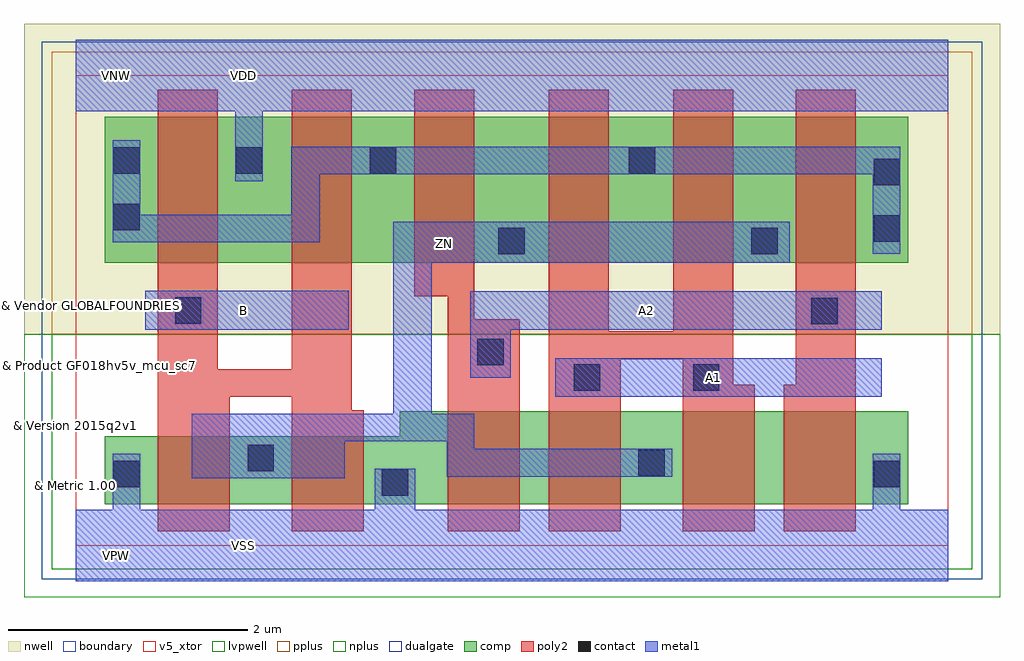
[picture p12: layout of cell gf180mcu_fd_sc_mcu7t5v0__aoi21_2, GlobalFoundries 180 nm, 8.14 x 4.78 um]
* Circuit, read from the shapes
.subckt gf180mcu_fd_sc_mcu7t5v0__aoi21_2 A1 A2 B VDD VNW VSS ZN
XM1 ZN B VSS VSUBS nfet_05v0 w=0.565u l=0.6u m=2
XM2 n1 A2 VSS VSUBS nfet_05v0 w=0.775u l=0.6u
XM3 ZN A1 n1 VSUBS nfet_05v0 w=0.775u l=0.6u
XM4 n2 A1 ZN VSUBS nfet_05v0 w=0.775u l=0.6u
XM5 VSS A2 n2 VSUBS nfet_05v0 w=0.775u l=0.6u
XM6 VDD B n3 VNW pfet_05v0 w=1.215u l=0.5u m=2
XM7 ZN A2 n3 VNW pfet_05v0 w=1.215u l=0.5u m=2
XM8 n3 A1 ZN VNW pfet_05v0 w=1.215u l=0.5u m=2
.ends

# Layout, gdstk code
import gdstk
lib = gdstk.Library(unit=1e-6, precision=1e-09)
def R(c, l, rs):  # rectangles x0, y0, x1, y1
    for r in rs: c.add(gdstk.rectangle(r[:2], r[2:], *l))
def P(c, l, *ps):  # polygons
    for p in ps: c.add(gdstk.Polygon(p, *l))
boundary = (0, 0)
nwell = (21, 0)
comp = (22, 0)
poly2 = (30, 0)
pplus = (31, 0)
nplus = (32, 0)
contact = (33, 0)
metal1 = (34, 0)
dualgate = (55, 0)
v5_xtor = (112, 1)
lvpwell = (204, 0)

gf180mcu_fd_sc_mcu7t5v0_ = lib.new_cell('gf180mcu_fd_sc_mcu7t5v0__aoi21_2')
R(gf180mcu_fd_sc_mcu7t5v0_, boundary, [(0,0,7.28,3.92)])
R(gf180mcu_fd_sc_mcu7t5v0_, nwell, [(-0.43,1.76,7.71,4.35)])
R(gf180mcu_fd_sc_mcu7t5v0_, comp, [(0.245,2.36,6.945,3.575)])
P(gf180mcu_fd_sc_mcu7t5v0_, comp, [(0.245,0.345),(0.245,0.91),(2.705,0.91),(2.705,1.12),(6.945,1.12),(6.945,0.345)])
P(gf180mcu_fd_sc_mcu7t5v0_, poly2, [(0.685,0.12),(0.685,3.8),(1.185,3.8),(1.185,1.47),(1.805,1.47),(1.805,3.8),(2.305,3.8),(2.305,1.13),(2.405,1.13),(2.405,0.12),(1.805,0.12),(1.805,1.24),(1.285,1.24),(1.285,0.12)],
  [(3.105,0.12),(3.105,2.08),(2.825,2.08),(2.825,3.8),(3.325,3.8),(3.325,1.885),(3.705,1.885),(3.705,0.12)],
  [(3.945,0.12),(3.945,3.8),(4.445,3.8),(4.445,1.785),(4.985,1.785),(4.985,3.8),(5.485,3.8),(5.485,1.34),(5.665,1.34),(5.665,0.12),(5.065,0.12),(5.065,1.555),(4.545,1.555),(4.545,0.12)],
  [(5.905,0.12),(5.905,1.34),(6.005,1.34),(6.005,3.8),(6.505,3.8),(6.505,0.12)])
R(gf180mcu_fd_sc_mcu7t5v0_, pplus, [(-0.2,1.76,7.48,4.12)])
R(gf180mcu_fd_sc_mcu7t5v0_, nplus, [(-0.2,-0.2,7.48,1.76)])
R(gf180mcu_fd_sc_mcu7t5v0_, contact, [(2.555,0.415,2.775,0.635), (0.315,0.485,0.535,0.705), (6.655,0.485,6.875,0.705), (4.695,0.58,4.915,0.8), (1.435,0.62,1.655,0.84), (4.155,1.29,4.375,1.51), (5.15,1.29,5.37,1.51), (3.35,1.505,3.57,1.725), (6.135,1.845,6.355,2.065), (0.83,1.85,1.05,2.07), (3.525,2.43,3.745,2.65), (5.635,2.43,5.855,2.65), (6.655,2.535,6.875,2.755), (0.315,2.63,0.535,2.85), (6.655,3.005,6.875,3.225), (0.315,3.1,0.535,3.32), (1.335,3.1,1.555,3.32), (2.455,3.1,2.675,3.32), (4.615,3.1,4.835,3.32)])
R(gf180mcu_fd_sc_mcu7t5v0_, metal1, [(4,1.24,6.725,1.56), (0.58,1.8,2.28,2.125)])
P(gf180mcu_fd_sc_mcu7t5v0_, metal1, [(0.97,0.56),(0.97,1.1),(2.65,1.1),(2.65,2.7),(5.955,2.7),(5.955,2.36),(2.97,2.36),(2.97,1.1),(3.325,1.1),(3.325,0.805),(4.975,0.805),(4.975,0.575),(3.095,0.575),(3.095,0.87),(2.245,0.87),(2.245,0.56)],
  [(3.29,1.4),(3.29,2.12),(6.725,2.12),(6.725,1.8),(3.63,1.8),(3.63,1.4)],
  [(6.65,2.435),(6.65,3.095),(2.035,3.095),(2.035,2.53),(0.31,2.53),(0.31,3.38),(0.54,3.38),(0.54,2.76),(1.8,2.76),(1.8,3.325),(6.88,3.325),(6.88,2.435)],
  [(0,-0.3),(0,0.3),(0.31,0.3),(0.31,0.765),(0.54,0.765),(0.54,0.3),(2.495,0.3),(2.495,0.64),(2.835,0.64),(2.835,0.3),(6.65,0.3),(6.65,0.765),(6.88,0.765),(6.88,0.3),(7.28,0.3),(7.28,-0.3)],
  [(1.33,3.04),(1.33,3.62),(0,3.62),(0,4.22),(7.28,4.22),(7.28,3.62),(1.56,3.62),(1.56,3.04)])
R(gf180mcu_fd_sc_mcu7t5v0_, dualgate, [(-0.28,-0.28,7.56,4.2)])
R(gf180mcu_fd_sc_mcu7t5v0_, v5_xtor, [(0,0,7.28,3.92)])
R(gf180mcu_fd_sc_mcu7t5v0_, lvpwell, [(-0.43,-0.43,7.71,1.76)])
gf180mcu_fd_sc_mcu7t5v0_.add(gdstk.Label('B', (1.4,1.96), layer=34, texttype=10))
gf180mcu_fd_sc_mcu7t5v0_.add(gdstk.Label('VDD', (1.4,3.92), layer=34, texttype=10))
gf180mcu_fd_sc_mcu7t5v0_.add(gdstk.Label('VSS', (1.4,0), layer=34, texttype=10))
gf180mcu_fd_sc_mcu7t5v0_.add(gdstk.Label('ZN', (3.08,2.52), layer=34, texttype=10))
gf180mcu_fd_sc_mcu7t5v0_.add(gdstk.Label('A1', (5.32,1.4), layer=34, texttype=10))
gf180mcu_fd_sc_mcu7t5v0_.add(gdstk.Label('A2', (4.76,1.96), layer=34, texttype=10))
gf180mcu_fd_sc_mcu7t5v0_.add(gdstk.Label('& Vendor GLOBALFOUNDRIES', (0,2), layer=63, texttype=63))
gf180mcu_fd_sc_mcu7t5v0_.add(gdstk.Label('& Product GF018hv5v_mcu_sc7', (0,1.5), layer=63, texttype=63))
gf180mcu_fd_sc_mcu7t5v0_.add(gdstk.Label('& Version 2015q2v1', (0,1), layer=63, texttype=63))
gf180mcu_fd_sc_mcu7t5v0_.add(gdstk.Label('& Metric 1.00', (0,0.5), layer=63, texttype=63))
gf180mcu_fd_sc_mcu7t5v0_.add(gdstk.Label('VNW', (0.345,3.92), layer=21, texttype=10))
gf180mcu_fd_sc_mcu7t5v0_.add(gdstk.Label('VPW', (0.34,-0.085), layer=204, texttype=10))

lib.write_gds('gf180mcu_fd_sc_mcu7t5v0__aoi21_2.gds')
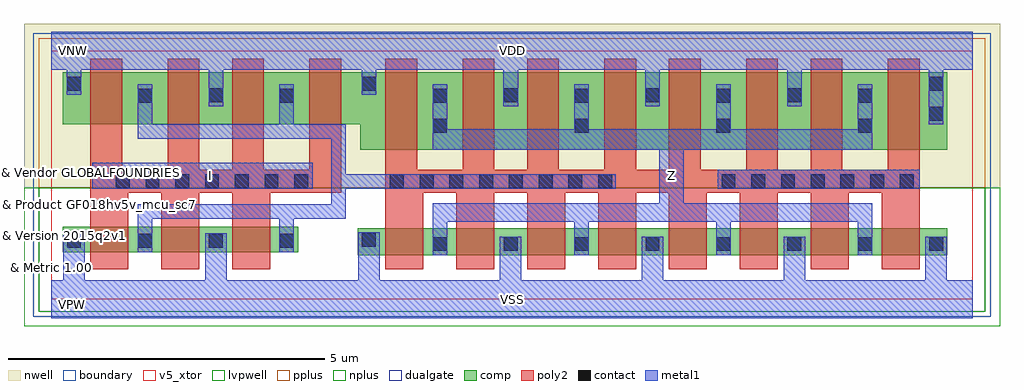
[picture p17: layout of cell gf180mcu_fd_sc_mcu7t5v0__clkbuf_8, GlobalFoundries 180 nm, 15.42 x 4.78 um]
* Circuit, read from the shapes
.subckt gf180mcu_fd_sc_mcu7t5v0__clkbuf_8 I VDD VNW VSS Z
XM1 n1 I VSS VSUBS nfet_05v0 w=0.405u l=0.6u m=3
XM2 Z n1 VSS VSUBS nfet_05v0 w=0.43u l=0.6u m=8
XM3 n1 I VDD VNW pfet_05v0 w=0.82u l=0.5u m=4
XM4 Z n1 VDD VNW pfet_05v0 w=1.22u l=0.5u m=8
.ends

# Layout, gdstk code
import gdstk
lib = gdstk.Library(unit=1e-6, precision=1e-09)
def R(c, l, rs):  # rectangles x0, y0, x1, y1
    for r in rs: c.add(gdstk.rectangle(r[:2], r[2:], *l))
def A(c, l, x, y, w, h, nx, ny, dx, dy):  # array of equal rectangles
    R(c, l, [(x+i*dx, y+j*dy, x+i*dx+w, y+j*dy+h) for i in range(nx) for j in range(ny)])
def P(c, l, *ps):  # polygons
    for p in ps: c.add(gdstk.Polygon(p, *l))
boundary = (0, 0)
nwell = (21, 0)
comp = (22, 0)
poly2 = (30, 0)
pplus = (31, 0)
nplus = (32, 0)
contact = (33, 0)
metal1 = (34, 0)
dualgate = (55, 0)
v5_xtor = (112, 1)
lvpwell = (204, 0)

gf180mcu_fd_sc_mcu7t5v0_ = lib.new_cell('gf180mcu_fd_sc_mcu7t5v0__clkbuf_8')
R(gf180mcu_fd_sc_mcu7t5v0_, boundary, [(0,0,14.56,3.92)])
R(gf180mcu_fd_sc_mcu7t5v0_, nwell, [(-0.43,1.76,14.99,4.35)])
R(gf180mcu_fd_sc_mcu7t5v0_, comp, [(4.84,0.69,14.16,1.12), (0.18,0.74,3.9,1.145)])
P(gf180mcu_fd_sc_mcu7t5v0_, comp, [(4.88,2.36),(4.88,2.76),(0.18,2.76),(0.18,3.58),(14.16,3.58),(14.16,2.36)])
P(gf180mcu_fd_sc_mcu7t5v0_, poly2, [(0.62,0.47),(0.62,3.8),(1.12,3.8),(1.12,2.04),(1.84,2.04),(1.84,3.8),(2.34,3.8),(2.34,2.04),(2.86,2.04),(2.86,3.8),(3.36,3.8),(3.36,2.04),(4.08,2.04),(4.08,3.8),(4.58,3.8),(4.58,1.68),(3.46,1.68),(3.46,0.47),(2.86,0.47),(2.86,1.68),(2.34,1.68),(2.34,0.47),(1.74,0.47),(1.74,1.68),(1.22,1.68),(1.22,0.47)],
  [(5.28,0.47),(5.28,3.8),(5.78,3.8),(5.78,2.04),(6.5,2.04),(6.5,3.8),(7,3.8),(7,2.04),(7.52,2.04),(7.52,3.8),(8.02,3.8),(8.02,2.04),(8.74,2.04),(8.74,3.8),(9.24,3.8),(9.24,2.04),(9.76,2.04),(9.76,3.8),(10.26,3.8),(10.26,2.04),(10.98,2.04),(10.98,3.8),(11.48,3.8),(11.48,2.04),(12,2.04),(12,3.8),(12.5,3.8),(12.5,2.04),(13.22,2.04),(13.22,3.8),(13.72,3.8),(13.72,0.47),(13.12,0.47),(13.12,1.68),(12.6,1.68),(12.6,0.47),(12,0.47),(12,1.68),(11.48,1.68),(11.48,0.47),(10.88,0.47),(10.88,1.68),(10.36,1.68),(10.36,0.47),(9.76,0.47),(9.76,1.68),(9.24,1.68),(9.24,0.47),(8.64,0.47),(8.64,1.68),(8.12,1.68),(8.12,0.47),(7.52,0.47),(7.52,1.68),(7,1.68),(7,0.47),(6.4,0.47),(6.4,1.68),(5.88,1.68),(5.88,0.47)])
R(gf180mcu_fd_sc_mcu7t5v0_, pplus, [(-0.2,1.76,14.76,4.12)])
R(gf180mcu_fd_sc_mcu7t5v0_, nplus, [(-0.2,-0.2,14.76,1.76)])
A(gf180mcu_fd_sc_mcu7t5v0_, contact, 6.03, 0.76, 0.22, 0.22, 8, 1, 1.12, 0)
A(gf180mcu_fd_sc_mcu7t5v0_, contact, 0.25, 0.81, 0.22, 0.22, 4, 1, 1.12, 0)
A(gf180mcu_fd_sc_mcu7t5v0_, contact, 1.02, 1.75, 0.22, 0.22, 7, 1, 0.47, 0)
A(gf180mcu_fd_sc_mcu7t5v0_, contact, 5.35, 1.75, 0.22, 0.22, 8, 1, 0.47, 0)
A(gf180mcu_fd_sc_mcu7t5v0_, contact, 10.59, 1.75, 0.22, 0.22, 7, 1, 0.47, 0)
A(gf180mcu_fd_sc_mcu7t5v0_, contact, 6.03, 2.63, 0.22, 0.22, 4, 2, 2.24, 0.47)
A(gf180mcu_fd_sc_mcu7t5v0_, contact, 7.15, 3.11, 0.22, 0.22, 3, 1, 2.24, 0)
R(gf180mcu_fd_sc_mcu7t5v0_, contact, [(4.91,0.83,5.13,1.05), (13.87,2.82,14.09,3.04), (1.37,3.1,1.59,3.32), (3.61,3.1,3.83,3.32), (2.49,3.11,2.71,3.33), (0.25,3.29,0.47,3.51), (4.91,3.29,5.13,3.51), (13.87,3.29,14.09,3.51)])
R(gf180mcu_fd_sc_mcu7t5v0_, metal1, [(10.53,1.74,13.72,2.04), (0.65,1.745,4.13,2.15)])
P(gf180mcu_fd_sc_mcu7t5v0_, metal1, [(1.365,0.74),(1.365,1.5),(4.425,1.5),(4.425,2.53),(1.365,2.53),(1.365,3.39),(1.595,3.39),(1.595,2.76),(3.605,2.76),(3.605,3.39),(3.835,3.39),(3.835,2.76),(4.655,2.76),(4.655,1.975),(8.92,1.975),(8.92,1.74),(4.655,1.74),(4.655,1.27),(3.835,1.27),(3.835,0.74),(3.605,0.74),(3.605,1.27),(1.595,1.27),(1.595,0.74)],
  [(6.025,0.69),(6.025,1.51),(9.61,1.51),(9.61,2.36),(6.025,2.36),(6.025,3.39),(6.255,3.39),(6.255,2.68),(8.265,2.68),(8.265,3.39),(8.495,3.39),(8.495,2.68),(10.505,2.68),(10.505,3.39),(10.735,3.39),(10.735,2.68),(12.745,2.68),(12.745,3.39),(12.975,3.39),(12.975,2.36),(9.99,2.36),(9.99,1.51),(12.975,1.51),(12.975,0.69),(12.745,0.69),(12.745,1.22),(10.735,1.22),(10.735,0.69),(10.505,0.69),(10.505,1.22),(8.495,1.22),(8.495,0.69),(8.265,0.69),(8.265,1.22),(6.255,1.22),(6.255,0.69)],
  [(0,-0.3),(0,0.3),(0.19,0.3),(0.19,1.04),(0.53,1.04),(0.53,0.3),(2.43,0.3),(2.43,1.04),(2.77,1.04),(2.77,0.3),(4.85,0.3),(4.85,1.055),(5.19,1.055),(5.19,0.3),(7.09,0.3),(7.09,0.985),(7.43,0.985),(7.43,0.3),(9.33,0.3),(9.33,0.985),(9.67,0.985),(9.67,0.3),(11.57,0.3),(11.57,0.985),(11.91,0.985),(11.91,0.3),(13.81,0.3),(13.81,0.985),(14.15,0.985),(14.15,0.3),(14.56,0.3),(14.56,-0.3)],
  [(13.865,2.76),(13.865,3.62),(11.855,3.62),(11.855,3.05),(11.625,3.05),(11.625,3.62),(9.615,3.62),(9.615,3.05),(9.385,3.05),(9.385,3.62),(7.375,3.62),(7.375,3.05),(7.145,3.05),(7.145,3.62),(5.135,3.62),(5.135,3.23),(4.905,3.23),(4.905,3.62),(2.715,3.62),(2.715,3.05),(2.485,3.05),(2.485,3.62),(0.475,3.62),(0.475,3.23),(0.245,3.23),(0.245,3.62),(0,3.62),(0,4.22),(14.56,4.22),(14.56,3.62),(14.095,3.62),(14.095,2.76)])
R(gf180mcu_fd_sc_mcu7t5v0_, dualgate, [(-0.28,-0.28,14.84,4.2)])
R(gf180mcu_fd_sc_mcu7t5v0_, v5_xtor, [(0,0,14.56,3.92)])
R(gf180mcu_fd_sc_mcu7t5v0_, lvpwell, [(-0.43,-0.43,14.99,1.76)])
gf180mcu_fd_sc_mcu7t5v0_.add(gdstk.Label('Z', (9.8,1.96), layer=34, texttype=10))
gf180mcu_fd_sc_mcu7t5v0_.add(gdstk.Label('VSS', (7.28,0), layer=34, texttype=10))
gf180mcu_fd_sc_mcu7t5v0_.add(gdstk.Label('VDD', (7.28,3.92), layer=34, texttype=10))
gf180mcu_fd_sc_mcu7t5v0_.add(gdstk.Label('I', (2.52,1.96), layer=34, texttype=10))
gf180mcu_fd_sc_mcu7t5v0_.add(gdstk.Label('& Vendor GLOBALFOUNDRIES', (0,2), layer=63, texttype=63))
gf180mcu_fd_sc_mcu7t5v0_.add(gdstk.Label('& Product GF018hv5v_mcu_sc7', (0,1.5), layer=63, texttype=63))
gf180mcu_fd_sc_mcu7t5v0_.add(gdstk.Label('& Version 2015q2v1', (0,1), layer=63, texttype=63))
gf180mcu_fd_sc_mcu7t5v0_.add(gdstk.Label('& Metric 1.00', (0,0.5), layer=63, texttype=63))
gf180mcu_fd_sc_mcu7t5v0_.add(gdstk.Label('VNW', (0.345,3.92), layer=21, texttype=10))
gf180mcu_fd_sc_mcu7t5v0_.add(gdstk.Label('VPW', (0.34,-0.085), layer=204, texttype=10))

lib.write_gds('gf180mcu_fd_sc_mcu7t5v0__clkbuf_8.gds')
